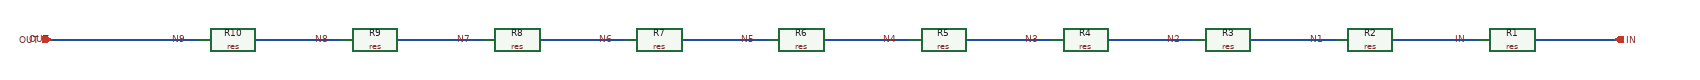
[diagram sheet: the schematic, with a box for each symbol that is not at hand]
v {xschem version=2.9.7 file_version=1.1}
G {}
V {}
S {}
E {}
N 2740 250 3000 250 {lab=IN}
C {devices/lab_wire.sym} 2740 250 0 0 {lab=IN}
N 2490 250 2760 250 {lab=N1}
C {devices/lab_wire.sym} 2490 250 0 0 {lab=N1}
N 2240 250 2510 250 {lab=N2}
C {devices/lab_wire.sym} 2240 250 0 0 {lab=N2}
N 1990 250 2260 250 {lab=N3}
C {devices/lab_wire.sym} 1990 250 0 0 {lab=N3}
N 1740 250 2010 250 {lab=N4}
C {devices/lab_wire.sym} 1740 250 0 0 {lab=N4}
N 1490 250 1760 250 {lab=N5}
C {devices/lab_wire.sym} 1490 250 0 0 {lab=N5}
N 1240 250 1510 250 {lab=N6}
C {devices/lab_wire.sym} 1240 250 0 0 {lab=N6}
N 990 250 1260 250 {lab=N7}
C {devices/lab_wire.sym} 990 250 0 0 {lab=N7}
N 740 250 1010 250 {lab=N8}
C {devices/lab_wire.sym} 740 250 0 0 {lab=N8}
N 490 250 760 250 {lab=N9}
C {devices/lab_wire.sym} 490 250 0 0 {lab=N9}
N 250 250 510 250 {lab=OUT}
C {devices/lab_wire.sym} 250 250 0 0 {lab=OUT}
C {devices/res.sym} 2750 250 0 0 {name=R1 value=1k}
C {devices/res.sym} 2500 250 0 0 {name=R2 value=1k}
C {devices/res.sym} 2250 250 0 0 {name=R3 value=1k}
C {devices/res.sym} 2000 250 0 0 {name=R4 value=1k}
C {devices/res.sym} 1750 250 0 0 {name=R5 value=1k}
C {devices/res.sym} 1500 250 0 0 {name=R6 value=1k}
C {devices/res.sym} 1250 250 0 0 {name=R7 value=1k}
C {devices/res.sym} 1000 250 0 0 {name=R8 value=1k}
C {devices/res.sym} 750 250 0 0 {name=R9 value=1k}
C {devices/res.sym} 500 250 0 0 {name=R10 value=1k}
C {devices/opin.sym} 3000 250 0 0 {lab=IN}
C {devices/ipin.sym} 250 250 0 0 {lab=OUT}
